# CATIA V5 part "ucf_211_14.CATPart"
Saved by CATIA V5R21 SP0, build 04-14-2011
Part number: ucf_211_14
Bounding box of the stored display mesh (mm): x -23.927 to -21.627, y -3.3 to 2.1, z 30.199 to 32.499
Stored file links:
  C:\TPO v2\SharedFS\Outgoing\ucf_211_14.CATPart

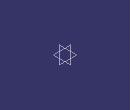
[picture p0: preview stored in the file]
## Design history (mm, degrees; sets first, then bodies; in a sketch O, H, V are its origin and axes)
AxisSystem1: origin (0, 0, 0), X (1, 0, 0), Y (0, 1, 0), Z (0, 0, 1)
Body1 "ucf_211_14" (main body)
  Solid1: solid without history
